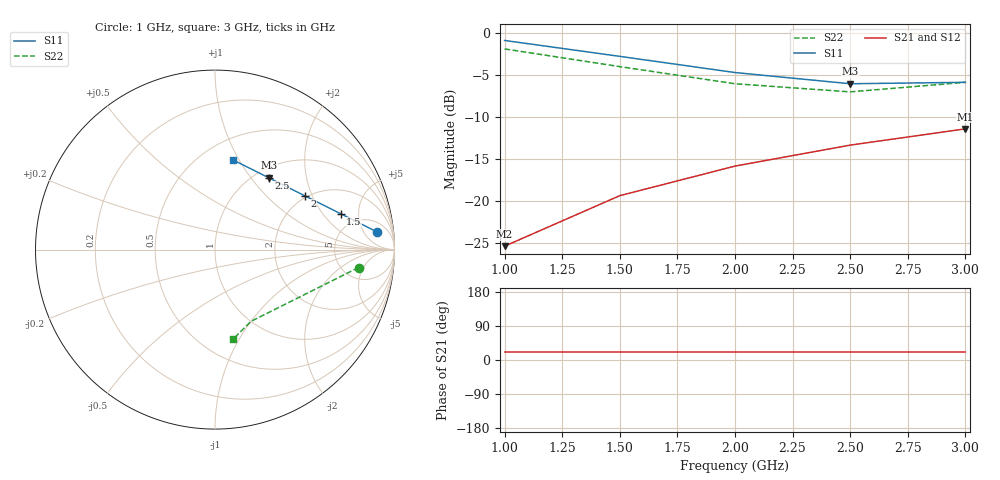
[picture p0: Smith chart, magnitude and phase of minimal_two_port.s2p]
! Minimal two-port Touchstone 1.0 fixture (hand-written, deterministic)
! Fixture for format_overview_service unit tests
# GHZ S RI R 50
! freq ReS11 ImS11 ReS21 ImS21 ReS12 ImS12 ReS22 ImS22
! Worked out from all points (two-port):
!   5 points, 1 GHz to 3 GHz, reference 50 ohm
!   highest |S21| = -11.40 dB at 3 GHz (marker M1); lowest = -25.4 dB at 1 GHz (marker M2)
!   |S21| within 3 dB of the highest: 2.288 GHz to end of sweep
!   lowest |S11| = -6.0 dB at 2.5 GHz (marker M3), VSWR 3.00, Z = 57.7 + j61.5 ohm
!   |S11| at or under -10 dB: nowhere
!   |S22| runs from -7.0 to -1.9 dB; largest |S21 - S12| = 0
!   S11 on the Smith chart (normalised r, x): 1 GHz: 9, +10; 1.5 GHz: 3.62, +3.08; 2 GHz: 1.94, +1.76; 2.5 GHz: 1.15, +1.23; 3 GHz: 0.70, +0.94
1  0.9 0.1  0.05 0.02  0.05 0.02  0.8 -0.1
1.5  0.7 0.2  0.1 0.04  0.1 0.04  0.6 -0.2
2  0.5 0.3  0.15 0.06  0.15 0.06  0.4 -0.3
2.5  0.3 0.4  0.2 0.08  0.2 0.08  0.2 -0.4
3  0.1 0.5  0.25 0.1  0.25 0.1  0.1 -0.5
